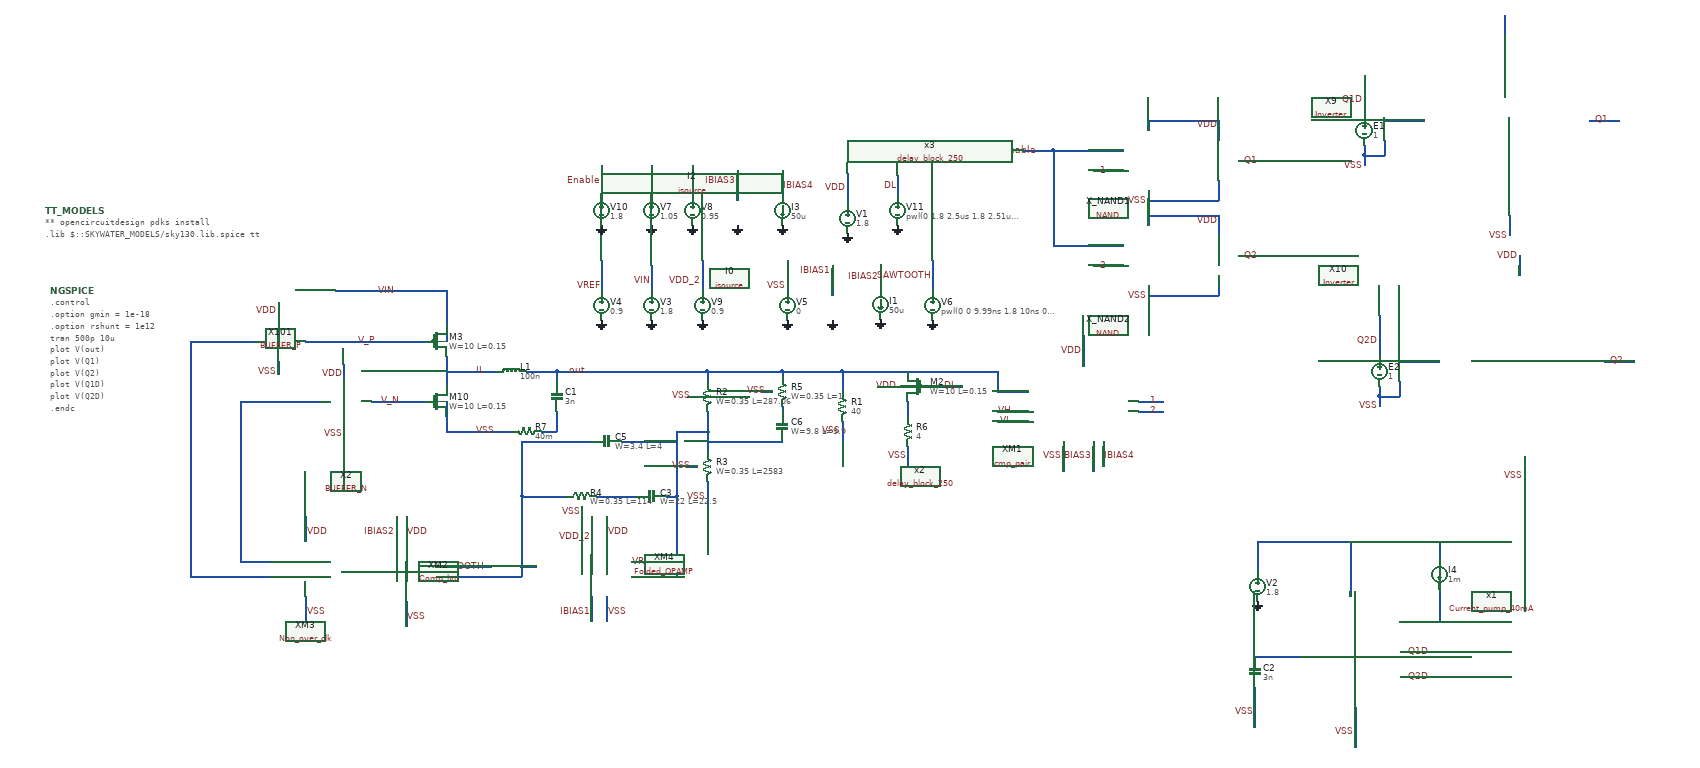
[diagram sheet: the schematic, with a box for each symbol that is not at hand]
v {xschem version=3.0.0 file_version=1.2 }
G {}
K {}
V {}
S {}
E {}
N 2432.5 810 2522.5 810 {
lab=Q1D}
N 2432.5 860 2532.5 860 {
lab=Q2D}
N 2332.5 600 2332.5 700 {
lab=#net1}
N 2342.5 920 2342.5 1000 {
lab=VSS}
N 530 220 530 280 {
lab=IL}
N 530 160 530 190 {
lab=VIN}
N 440 190 490 190 {
lab=V_P}
N 530 90 530 160 {
lab=VIN}
N 310 90 530 90 {
lab=VIN}
N 530 340 530 370 {
lab=VSS}
N 530 250 590 250 {
lab=IL}
N 590 250 630 250 {
lab=IL}
N 750 250 750 270 {
lab=out}
N 690 250 750 250 {
lab=out}
N 750 330 750 370 {
lab=#net2}
N 750 250 860 250 {
lab=out}
N 850 540 850 590 {
lab=VDD}
N 820 540 820 590 {
lab=VDD_2}
N 850 700 850 750 {
lab=VSS}
N 820 700 820 750 {
lab=IBIAS1}
N 900 660 950 660 {
lab=#net3}
N 900 630 950 630 {
lab=VREF}
N 940 40 940 90 {
lab=VIN}
N 1040 30 1040 90 {
lab=VDD_2}
N 2147.5 640 2147.5 650 {
lab=#net1}
N 2147.5 590 2147.5 640 {
lab=#net1}
N 1210 60 1210 80 {
lab=VSS}
N 1210 80 1210 90 {
lab=VSS}
N 1210 30 1210 60 {
lab=VSS}
N 1300 40 1300 100 {
lab=IBIAS1}
N 450 540 450 590 {
lab=VDD}
N 450 710 450 760 {
lab=VSS}
N 840 60 840 80 {
lab=VREF}
N 840 80 840 90 {
lab=VREF}
N 840 30 840 60 {
lab=VREF}
N 950 660 980 660 {
lab=#net3}
N 430 540 430 590 {
lab=IBIAS2}
N 1500 30 1500 90 {
lab=SAWTOOTH}
N 250 190 440 190 {
lab=V_P}
N 860 250 1040 250 {
lab=out}
N 1050 250 1050 270 {
lab=out}
N 1050 330 1050 380 {
lab=#net3}
N 1050 470 1050 520 {
lab=VSS}
N 830 500 910 500 {
lab=#net4}
N 680 500 770 500 {
lab=#net5}
N 680 500 680 640 {
lab=#net5}
N 990 500 990 630 {
lab=#net3}
N 970 500 990 500 {
lab=#net3}
N 680 390 820 390 {
lab=#net5}
N 880 390 990 390 {
lab=#net3}
N 990 430 990 500 {
lab=#net3}
N 680 640 710 640 {
lab=#net5}
N 990 630 990 660 {
lab=#net3}
N 980 660 990 660 {
lab=#net3}
N 1050 250 1200 250 {
lab=out}
N 1200 250 1200 260 {
lab=out}
N 1200 320 1200 330 {
lab=#net6}
N 1040 250 1050 250 {
lab=out}
N 990 370 990 430 {
lab=#net3}
N 990 370 1050 370 {
lab=#net3}
N 1050 380 1050 410 {
lab=#net3}
N 1320 250 1320 290 {
lab=out}
N 1200 250 1320 250 {
lab=out}
N 1320 350 1320 390 {
lab=VSS}
N 510 660 680 660 {
lab=#net5}
N 680 640 680 660 {
lab=#net5}
N 440 310 490 310 {
lab=V_N}
N 530 310 530 340 {
lab=VSS}
N 1320 250 1450 250 {
lab=out}
N 1450 400 1450 440 {
lab=VSS}
N 1450 310 1450 340 {
lab=#net7}
N 1490 280 1560 280 {
lab=DL}
N 250 540 250 590 {
lab=VDD}
N 250 700 250 750 {
lab=VSS}
N 20 190 150 190 {
lab=#net8}
N 20 190 20 630 {
lab=#net8}
N 195 230 195 257.5 {
lab=VSS}
N 195 112.5 195 147.5 {
lab=VDD}
N 380 310 440 310 {
lab=V_N}
N 120 310 280 310 {
lab=#net9}
N 120 310 120 400 {
lab=#net9}
N 325 350 325 387.5 {
lab=VSS}
N 325 237.5 325 267.5 {
lab=VDD}
N 120 630 180 630 {
lab=#net9}
N 120 400 120 630 {
lab=#net9}
N 20 660 180 660 {
lab=#net8}
N 20 630 20 660 {
lab=#net8}
N 680 390 680 500 {
lab=#net5}
N 1050 390 1100 390 {
lab=#net3}
N 1100 390 1200 390 {
lab=#net3}
N 850 700 850 750 {
lab=VSS}
N 1390 280 1450 280 {
lab=VDD}
N 1395 37.5 1395 87.5 {
lab=IBIAS2}
N 330 650 380 650 {
lab=#net10}
N 510 640 620 640 {
lab=SAWTOOTH}
N 800 520 800 540 {
lab=VSS}
N 1160 290 1180 290 {
lab=VSS}
N 1010 300 1030 300 {
lab=VSS}
N 1010 440 1030 440 {
lab=VSS}
N 530 370 660 370 {
lab=VSS}
N 720 370 750 370 {
lab=#net2}
N 320 650 330 650 {
lab=#net10}
N 1910 310 1960 310 {
lab=1}
N 1910 330 1960 330 {
lab=2}
N 1840 390 1840 440 {
lab=IBIAS4}
N 1820 390 1820 450 {
lab=IBIAS3}
N 1760 390 1760 450 {
lab=VSS}
N 1800 180 1800 240 {
lab=VDD}
N 1630 290 1690 290 {
lab=out}
N 1630 330 1690 330 {
lab=VH}
N 1630 350 1690 350 {
lab=VL}
N 1630 250 1630 290 {
lab=out}
N 940 -160 940 -100 {
lab=VH}
N 1020 -160 1020 -100 {
lab=VL}
N 1110 -150 1110 -90 {
lab=IBIAS3}
N 1200 -150 1200 -100 {
lab=IBIAS4}
N 1740 0 1880 0 {
lab=Enable}
N 1740 -190 1880 -190 {
lab=Enable}
N 1680 -190 1740 -190 {
lab=Enable}
N 1820 -150 1880 -150 {
lab=1}
N 1820 40 1880 40 {
lab=2}
N 2110 -170 2170 -170 {
lab=Q1}
N 2110 20 2170 20 {
lab=Q2}
N 2170 -170 2180 -170 {
lab=Q1}
N 840 -160 840 -100 {
lab=Enable}
N 1430 -120 1430 -100 {
lab=DL}
N 1430 -140 1430 -120 {
lab=DL}
N 1450 250 1630 250 {
lab=out}
N 1930 80 1930 100 {
lab=VSS}
N 1930 100 2070 100 {
lab=VSS}
N 2070 60 2070 100 {
lab=VSS}
N 1930 -60 1930 -40 {
lab=VDD}
N 1930 -60 2070 -60 {
lab=VDD}
N 2070 -60 2070 -20 {
lab=VDD}
N 1930 -110 1930 -90 {
lab=VSS}
N 1930 -90 2070 -90 {
lab=VSS}
N 2070 -130 2070 -90 {
lab=VSS}
N 1930 -250 1930 -230 {
lab=VDD}
N 1930 -250 2070 -250 {
lab=VDD}
N 2070 -250 2070 -210 {
lab=VDD}
N 1740 -190 1740 0 {
lab=Enable}
N 2142.5 820 2232.5 820 {
lab=#net11}
N 2147.5 590 2332.5 590 {
lab=#net1}
N 2332.5 590 2332.5 600 {
lab=#net1}
N 1330 -95 1330 -85 {
lab=VDD}
N 1330 -145 1330 -95 {
lab=VDD}
N 2400 -250 2480 -250 {
lab=#net12}
N 2430 230 2510 230 {
lab=#net13}
N 2142.5 880 2142.5 960 {
lab=VSS}
N 2360 -340 2360 -260 {
lab=Q1D}
N 2400 -210 2400 -180 {
lab=VSS}
N 2360 -180 2400 -180 {
lab=VSS}
N 2360 -200 2360 -180 {
lab=VSS}
N 2360 -180 2360 -160 {
lab=VSS}
N 2390 140 2390 220 {
lab=Q2D}
N 2430 270 2430 300 {
lab=VSS}
N 2390 300 2430 300 {
lab=VSS}
N 2390 280 2390 300 {
lab=VSS}
N 2390 300 2390 320 {
lab=VSS}
N 2430 750 2510 750 {
lab=#net14}
N 2510 590 2510 630 {
lab=#net1}
N 2330 590 2510 590 {
lab=#net1}
N 2510 685 2510 750 {
lab=#net14}
N 2680 420 2680 440 {
lab=VSS}
N 2680 440 2680 460 {
lab=VSS}
N 2670 40 2670 60 {
lab=VDD}
N 2670 20 2670 40 {
lab=VDD}
N 2840 230 2900 230 {
lab=Q2}
N 2650 -60 2650 -40 {
lab=VSS}
N 2650 -40 2650 -20 {
lab=VSS}
N 2640 -440 2640 -420 {
lab=#net15}
N 2640 -460 2640 -440 {
lab=#net15}
N 2810 -250 2870 -250 {
lab=Q2}
C {devices/code.sym} -270 -70 0 0 {name=TT_MODELS
only_toplevel=true
format="tcleval( @value )"
value="
** opencircuitdesign pdks install
.lib $::SKYWATER_MODELS/sky130.lib.spice tt

"
spice_ignore=false}
C {devices/code_shown.sym} -260 90 0 0 {name=NGSPICE
only_toplevel=true
value="

.control

.option gmin = 1e-18
.option rshunt = 1e12
tran 500p 10u

plot V(out)
plot V(Q1)
plot V(Q2) 
plot V(Q1D)
plot V(Q2D)
.endc
" }
C {devices/lab_wire.sym} 2492.5 810 0 0 {name=l76 sig_type=std_logic lab=Q1D}
C {devices/lab_wire.sym} 2492.5 860 0 0 {name=l77 sig_type=std_logic lab=Q2D}
C {devices/lab_pin.sym} 2342.5 970 0 0 {name=l80 sig_type=std_logic lab=VSS}
C {sky130_fd_pr/pfet_01v8.sym} 510 190 0 0 {name=M3
L=0.15
W=10
nf=1
mult=450
ad="'int((nf+1)/2) * W/nf * 0.29'" 
pd="'2*int((nf+1)/2) * (W/nf + 0.29)'"
as="'int((nf+2)/2) * W/nf * 0.29'" 
ps="'2*int((nf+2)/2) * (W/nf + 0.29)'"
nrd="'0.29 / W'" nrs="'0.29 / W'"
sa=0 sb=0 sd=0
model=pfet_01v8
spiceprefix=X
}
C {devices/ind.sym} 660 250 3 0 {name=L1
m=1
value=100n
footprint=1206
device=inductor}
C {devices/capa.sym} 750 300 0 0 {name=C1
m=1
value=3n
footprint=1206
device="ceramic capacitor"}
C {devices/lab_wire.sym} 810 250 0 0 {name=l4 sig_type=std_logic lab=out}
C {devices/lab_wire.sym} 610 250 0 0 {name=l6 sig_type=std_logic lab=IL}
C {devices/lab_wire.sym} 430 90 0 0 {name=l5 sig_type=std_logic lab=VIN}
C {devices/vsource.sym} 940 120 0 0 {name=V3 value=1.8}
C {devices/gnd.sym} 940 150 0 0 {name=l7 lab=GND}
C {devices/lab_wire.sym} 940 70 0 0 {name=l2 sig_type=std_logic lab=VIN}
C {devices/gnd.sym} 1300 150 0 0 {name=l19 lab=GND}
C {devices/lab_wire.sym} 1300 50 0 0 {name=l22 sig_type=std_logic lab=IBIAS1}
C {devices/isource.sym} 1300 120 0 0 {name=I0 value=50u}
C {devices/vsource.sym} 1040 120 0 0 {name=V9 value=0.9}
C {devices/gnd.sym} 1040 150 0 0 {name=l42 lab=GND}
C {devices/lab_wire.sym} 1040 70 0 0 {name=l8 sig_type=std_logic lab=VDD_2}
C {devices/vsource.sym} 2147.5 680 0 0 {name=V2 value=1.8}
C {devices/gnd.sym} 2147.5 710 0 0 {name=l18 lab=GND}
C {devices/vsource.sym} 1210 120 0 0 {name=V5 value=0}
C {devices/gnd.sym} 1210 150 0 0 {name=l26 lab=GND}
C {devices/lab_wire.sym} 1210 80 0 0 {name=l10 sig_type=std_logic lab=VSS}
C {devices/lab_wire.sym} 850 570 0 1 {name=l13 sig_type=std_logic lab=VDD}
C {devices/lab_wire.sym} 820 580 0 0 {name=l14 sig_type=std_logic lab=VDD_2}
C {devices/lab_wire.sym} 630 370 0 0 {name=l1 sig_type=std_logic lab=VSS}
C {devices/lab_wire.sym} 850 730 0 1 {name=l15 sig_type=std_logic lab=VSS}
C {devices/lab_wire.sym} 820 730 0 0 {name=l16 sig_type=std_logic lab=IBIAS1}
C {devices/lab_wire.sym} 450 570 0 1 {name=l11 sig_type=std_logic lab=VDD}
C {devices/lab_wire.sym} 450 740 0 1 {name=l12 sig_type=std_logic lab=VSS}
C {devices/vsource.sym} 840 120 0 0 {name=V4 value=0.9}
C {devices/gnd.sym} 840 150 0 0 {name=l17 lab=GND}
C {devices/lab_wire.sym} 840 80 0 0 {name=l20 sig_type=std_logic lab=VREF}
C {devices/isource.sym} 1395 117.5 0 1 {name=I1 value=50u}
C {devices/lab_wire.sym} 430 570 0 0 {name=l27 sig_type=std_logic lab=IBIAS2}
C {devices/vsource.sym} 1500 120 0 0 {name=V6 value="pwl(0 0 9.99ns 1.8 10ns 0) r=0"}
C {devices/gnd.sym} 1500 150 0 0 {name=l28 lab=GND}
C {devices/gnd.sym} 1500 150 0 0 {name=l29 lab=GND}
C {devices/lab_wire.sym} 1500 60 0 0 {name=l30 sig_type=std_logic lab=SAWTOOTH}
C {devices/lab_wire.sym} 1050 500 0 0 {name=l31 sig_type=std_logic lab=VSS}
C {devices/lab_wire.sym} 950 630 0 0 {name=l33 sig_type=std_logic lab=VREF}
C {devices/lab_wire.sym} 610 640 0 0 {name=l32 sig_type=std_logic lab=SAWTOOTH}
C {devices/lab_wire.sym} 1320 370 0 0 {name=l21 sig_type=std_logic lab=VSS}
C {sky130_fd_pr/pfet_01v8.sym} 1470 280 0 1 {name=M2
L=0.15
W=10
nf=1
mult=450
ad="'int((nf+1)/2) * W/nf * 0.29'" 
pd="'2*int((nf+1)/2) * (W/nf + 0.29)'"
as="'int((nf+2)/2) * W/nf * 0.29'" 
ps="'2*int((nf+2)/2) * (W/nf + 0.29)'"
nrd="'0.29 / W'" nrs="'0.29 / W'"
sa=0 sb=0 sd=0
model=pfet_01v8
spiceprefix=X
}
C {devices/lab_wire.sym} 1450 420 0 0 {name=l23 sig_type=std_logic lab=VSS}
C {devices/lab_wire.sym} 250 570 0 1 {name=l35 sig_type=std_logic lab=VDD}
C {devices/lab_wire.sym} 250 730 0 1 {name=l37 sig_type=std_logic lab=VSS}
C {DC_DC_Converter/BUFFER/BUFFER_PMOS/BUFFER_P.sym} 130 240 0 0 {name=X101}
C {devices/lab_wire.sym} 195 130 0 0 {name=l38 sig_type=std_logic lab=VDD}
C {devices/lab_wire.sym} 195 252.5 0 0 {name=l40 sig_type=std_logic lab=VSS}
C {DC_DC_Converter/BUFFER/BUFFER_NMOS/BUFFER_N.sym} 190 390 0 0 {name=X2}
C {devices/lab_wire.sym} 325 375 0 0 {name=l39 sig_type=std_logic lab=VSS}
C {devices/lab_wire.sym} 325 255 0 0 {name=l41 sig_type=std_logic lab=VDD}
C {DC_DC_Converter/Non_Overlap_Clk/Non_over_clk.sym} 450 910 0 1 {name=XM3}
C {devices/lab_wire.sym} 390 190 0 0 {name=l3 sig_type=std_logic lab=V_P}
C {devices/lab_wire.sym} 440 310 0 0 {name=l43 sig_type=std_logic lab=V_N}
C {DC_DC_Converter/Folded_OPAMP/Folded_OPAMP.sym} 910 700 0 1 {name=XM4}
C {devices/lab_wire.sym} 1550 280 0 0 {name=l96 sig_type=std_logic lab=DL}
C {sky130_fd_pr/cap_mim_m3_1.sym} 850 390 3 0 {name=C5 model=cap_mim_m3_1 W=3.4 L=4 MF=1 spiceprefix=X}
C {sky130_fd_pr/cap_mim_m3_1.sym} 940 500 3 0 {name=C3 model=cap_mim_m3_1 W=22 L=22.5 MF=1 spiceprefix=X}
C {sky130_fd_pr/cap_mim_m3_1.sym} 1200 360 0 0 {name=C6 model=cap_mim_m3_1 W=9.8 L=9.9 MF=1 spiceprefix=X}
C {devices/lab_wire.sym} 1430 280 0 0 {name=l98 sig_type=std_logic lab=VDD}
C {sky130_fd_pr/nfet_01v8.sym} 510 310 0 0 {name=M10
L=0.15
W=10
nf=1 
mult=150
ad="'int((nf+1)/2) * W/nf * 0.29'" 
pd="'2*int((nf+1)/2) * (W/nf + 0.29)'"
as="'int((nf+2)/2) * W/nf * 0.29'" 
ps="'2*int((nf+2)/2) * (W/nf + 0.29)'"
nrd="'0.29 / W'" nrs="'0.29 / W'"
sa=0 sb=0 sd=0
model=nfet_01v8
spiceprefix=X
}
C {devices/lab_wire.sym} 1395 62.5 0 0 {name=l24 sig_type=std_logic lab=IBIAS2}
C {sky130_fd_pr/res_high_po_0p35.sym} 800 500 3 0 {name=R4
W=0.35
L=114
model=res_high_po_0p35
spiceprefix=X
mult=58}
C {devices/lab_wire.sym} 800 530 3 0 {name=l9 sig_type=std_logic lab=VSS}
C {sky130_fd_pr/res_high_po_0p35.sym} 1200 290 0 0 {name=R5
W=0.35
L=1
model=res_high_po_0p35
spiceprefix=X
mult=1}
C {devices/lab_wire.sym} 1170 290 0 0 {name=l44 sig_type=std_logic lab=VSS}
C {sky130_fd_pr/res_high_po_0p35.sym} 1050 300 0 0 {name=R2
W=0.35
L=287.06
model=res_high_po_0p35
spiceprefix=X
mult=1}
C {devices/lab_wire.sym} 1020 300 0 0 {name=l45 sig_type=std_logic lab=VSS}
C {sky130_fd_pr/res_high_po_0p35.sym} 1050 440 0 0 {name=R3
W=0.35
L=2583
model=res_high_po_0p35
spiceprefix=X
mult=1}
C {devices/lab_wire.sym} 1020 440 0 0 {name=l46 sig_type=std_logic lab=VSS}
C {devices/res.sym} 690 370 1 0 {name=R7
value=40m
footprint=1206
device=resistor
m=1}
C {devices/res.sym} 1320 320 0 0 {name=R1
value=40
footprint=1206
device=resistor
m=1}
C {devices/res.sym} 1450 370 0 0 {name=R6
value=4
footprint=1206
device=resistor
m=1}
C {DC_DC_Converter/Comparator/Comp_lvt.sym} 530 720 0 1 {name=XM2}
C {devices/lab_wire.sym} 1840 420 0 1 {name=l48 sig_type=std_logic lab=IBIAS4}
C {devices/lab_wire.sym} 1820 420 0 0 {name=l49 sig_type=std_logic lab=IBIAS3}
C {devices/lab_pin.sym} 1760 420 0 0 {name=l50 sig_type=std_logic lab=VSS}
C {devices/lab_pin.sym} 1800 210 0 0 {name=l51 sig_type=std_logic lab=VDD}
C {devices/lab_pin.sym} 1660 330 1 0 {name=l53 sig_type=std_logic lab=VH}
C {devices/lab_pin.sym} 1660 350 3 0 {name=l54 sig_type=std_logic lab=VL}
C {DC_DC_Converter/Comparator_Pair/cmp_pair.sym} 1670 390 0 0 {name=XM1}
C {devices/lab_wire.sym} 1950 310 0 0 {name=l47 sig_type=std_logic lab=1}
C {devices/lab_wire.sym} 1950 330 0 0 {name=l87 sig_type=std_logic lab=2}
C {devices/vsource.sym} 940 -70 0 0 {name=V7 value=1.05}
C {devices/gnd.sym} 940 -40 0 0 {name=l52 lab=GND}
C {devices/lab_pin.sym} 940 -130 0 0 {name=l55 sig_type=std_logic lab=VH}
C {devices/vsource.sym} 1020 -70 0 0 {name=V8 value=0.95}
C {devices/gnd.sym} 1020 -40 0 0 {name=l56 lab=GND}
C {devices/lab_pin.sym} 1020 -130 0 0 {name=l57 sig_type=std_logic lab=VL}
C {devices/gnd.sym} 1110 -40 0 0 {name=l58 lab=GND}
C {devices/isource.sym} 1110 -70 0 0 {name=I2 value=50u}
C {devices/isource.sym} 1200 -70 0 0 {name=I3 value=50u}
C {devices/gnd.sym} 1200 -40 0 0 {name=l60 lab=GND}
C {devices/lab_wire.sym} 1110 -130 0 0 {name=l59 sig_type=std_logic lab=IBIAS3}
C {devices/lab_wire.sym} 1200 -120 0 1 {name=l61 sig_type=std_logic lab=IBIAS4}
C {devices/noconn.sym} 1960 330 0 1 {name=l62}
C {devices/noconn.sym} 1960 310 0 1 {name=l63}
C {DC_DC_Converter/NAND_GATE/NAND.sym} 1860 -100 0 0 {name=X_NAND1}
C {DC_DC_Converter/NAND_GATE/NAND.sym} 1860 90 0 0 {name=X_NAND2}
C {devices/lab_pin.sym} 1930 100 0 0 {name=l84 sig_type=std_logic lab=VSS}
C {DC_DC_Converter/Inverter/Inverter.sym} 2000 -150 0 0 {name=X9}
C {DC_DC_Converter/Inverter/Inverter.sym} 2000 40 0 0 {name=X10}
C {devices/lab_wire.sym} 2150 20 0 0 {name=l86 sig_type=std_logic lab=Q2}
C {devices/lab_wire.sym} 1850 -150 0 0 {name=l64 sig_type=std_logic lab=1}
C {devices/lab_wire.sym} 1850 40 0 0 {name=l88 sig_type=std_logic lab=2}
C {devices/lab_wire.sym} 1710 -190 0 0 {name=l91 sig_type=std_logic lab=Enable}
C {devices/lab_pin.sym} 2070 -50 0 0 {name=l94 sig_type=std_logic lab=VDD}
C {devices/lab_wire.sym} 2150 -170 0 0 {name=l79 sig_type=std_logic lab=Q1}
C {devices/gnd.sym} 840 -40 0 0 {name=l89 lab=GND}
C {devices/lab_pin.sym} 840 -130 0 0 {name=l90 sig_type=std_logic lab=Enable}
C {devices/vsource.sym} 840 -70 0 0 {name=V10 value=1.8}
C {devices/gnd.sym} 1395 147.5 0 0 {name=l25 lab=GND}
C {devices/vsource.sym} 1430 -70 0 0 {name=V11 value="pwl(0 1.8 2.5us 1.8 2.51us 0 5us 0) r=0"}
C {devices/gnd.sym} 1430 -40 0 0 {name=l65 lab=GND}
C {devices/gnd.sym} 1430 -40 0 0 {name=l66 lab=GND}
C {devices/lab_wire.sym} 1430 -120 0 0 {name=l67 sig_type=std_logic lab=DL}
C {devices/lab_pin.sym} 1930 -90 0 0 {name=l34 sig_type=std_logic lab=VSS}
C {devices/lab_pin.sym} 2070 -240 0 0 {name=l36 sig_type=std_logic lab=VDD}
C {devices/vsource.sym} 1330 -55 0 0 {name=V1 value=1.8}
C {devices/gnd.sym} 1330 -25 0 0 {name=l78 lab=GND}
C {devices/lab_wire.sym} 1330 -115 0 0 {name=l82 sig_type=std_logic lab=VDD}
C {devices/capa.sym} 2142.5 850 0 0 {name=C2
m=1
value=3n
footprint=1206
device="ceramic capacitor"}
C {devices/lab_pin.sym} 2142.5 930 0 0 {name=l81 sig_type=std_logic lab=VSS}
C {devices/vcvs.sym} 2360 -230 0 1 {name=E1 value=1}
C {devices/lab_wire.sym} 2360 -290 1 0 {name=l83 sig_type=std_logic lab=Q1D}
C {devices/lab_pin.sym} 2360 -160 0 0 {name=l85 sig_type=std_logic lab=VSS}
C {devices/vcvs.sym} 2390 250 0 1 {name=E2 value=1}
C {devices/lab_pin.sym} 2390 320 0 0 {name=l92 sig_type=std_logic lab=VSS}
C {devices/lab_wire.sym} 2390 190 1 0 {name=l73 sig_type=std_logic lab=Q2D}
C {DC_DC_Converter/Current_pump_mirror/Current_pump_40mA.sym} 2672.5 800 0 1 {name=x1}
C {devices/isource.sym} 2510 655 0 0 {name=I4 value=1m}
C {DC_DC_Converter/Delay_block_revised/delay_block_250.sym} 1540 360 0 1 {name=x2}
C {devices/lab_pin.sym} 2680 460 0 0 {name=l68 sig_type=std_logic lab=VSS}
C {devices/lab_pin.sym} 2670 20 2 1 {name=l69 sig_type=std_logic lab=VDD}
C {devices/lab_wire.sym} 2880 230 0 0 {name=l70 sig_type=std_logic lab=Q2}
C {DC_DC_Converter/Delay_block_revised/delay_block_250.sym} 1510 -120 0 1 {name=x3}
C {devices/lab_pin.sym} 2650 -20 0 0 {name=l71 sig_type=std_logic lab=VSS}
C {devices/lab_wire.sym} 2850 -250 0 0 {name=l72 sig_type=std_logic lab=Q1}
